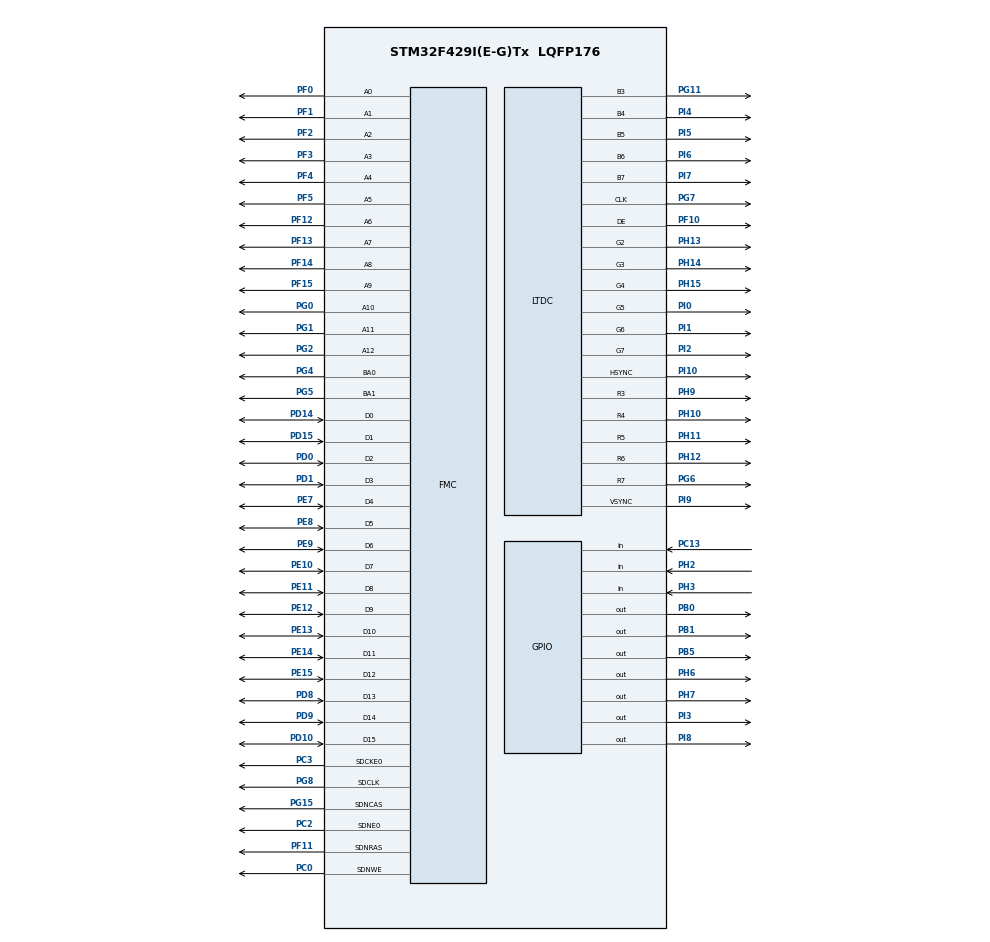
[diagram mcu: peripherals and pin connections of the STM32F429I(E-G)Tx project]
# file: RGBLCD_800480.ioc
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DMA2D.ColorMode=DMA2D_OUTPUT_RGB565
FMC.CASLatency1=FMC_SDRAM_CAS_LATENCY_3
FMC.ColumnBitsNumber1=FMC_SDRAM_COLUMN_BITS_NUM_9
FMC.ExitSelfRefreshDelay1=8
FMC.LoadToActiveDelay1=2
FMC.RCDDelay1=2
FMC.RPDelay1=2
FMC.RPDelay2=2
FMC.ReadBurst1=FMC_SDRAM_RBURST_ENABLE
FMC.ReadBurst2=FMC_SDRAM_RBURST_ENABLE
FMC.ReadPipeDelay1=FMC_SDRAM_RPIPE_DELAY_1
FMC.ReadPipeDelay2=FMC_SDRAM_RPIPE_DELAY_1
FMC.RowCycleDelay1=6
FMC.RowCycleDelay2=6
FMC.SDClockPeriod1=FMC_SDRAM_CLOCK_PERIOD_2
FMC.SDClockPeriod2=FMC_SDRAM_CLOCK_PERIOD_2
FMC.SelfRefreshTime1=6
FMC.WriteRecoveryTime1=4
LTDC.ActiveW=800
LTDC.Alpha_L0=255
LTDC.FBStartAdress_L0=0xC0000000
LTDC.HBP=88
LTDC.HFP=40
LTDC.HSync=1
LTDC.ImageHeight_L0=480
LTDC.ImageWidth_L0=800
LTDC.PixelFormat_L0=LTDC_PIXEL_FORMAT_RGB565
LTDC.PixelFormat_L1=LTDC_PIXEL_FORMAT_RGB565
LTDC.VBP=32
LTDC.VFP=13
LTDC.VSync=48
LTDC.WindowX1_L0=800
LTDC.WindowY1_L0=480
Mcu.Family=STM32F4
Mcu.Name=STM32F429I(E-G)Tx
Mcu.Package=LQFP176
NVIC.PriorityGroup=NVIC_PRIORITYGROUP_4
PA13.Mode=Serial_Wire
PA13.Signal=SYS_JTMS-SWDIO
PA14.Mode=Serial_Wire
PA14.Signal=SYS_JTCK-SWCLK
PB0.Signal=GPIO_Output
PB1.Signal=GPIO_Output
PB5.Signal=GPIO_Output
PC0.Signal=FMC_SDNWE
PC13.GPIO_PuPd=GPIO_PULLDOWN
PC13.Signal=GPIO_Input
PC2.Mode=SdramChipSelect1_1
PC2.Signal=FMC_SDNE0
PC3.Mode=SdramChipSelect1_1
PC3.Signal=FMC_SDCKE0
PD0.Signal=FMC_D2_DA2
PD1.Signal=FMC_D3_DA3
PD10.Signal=FMC_D15_DA15
PD14.Signal=FMC_D0_DA0
PD15.Signal=FMC_D1_DA1
PD8.Signal=FMC_D13_DA13
PD9.Signal=FMC_D14_DA14
PE10.Signal=FMC_D7_DA7
PE11.Signal=FMC_D8_DA8
PE12.Signal=FMC_D9_DA9
PE13.Signal=FMC_D10_DA10
PE14.Signal=FMC_D11_DA11
PE15.Signal=FMC_D12_DA12
PE7.Signal=FMC_D4_DA4
PE8.Signal=FMC_D5_DA5
PE9.Signal=FMC_D6_DA6
PF0.Signal=FMC_A0
PF1.Signal=FMC_A1
PF10.GPIO_Speed=GPIO_SPEED_FREQ_HIGH
PF10.Mode=RGB565
PF10.Signal=LTDC_DE
PF11.Signal=FMC_SDNRAS
PF12.Signal=FMC_A6
PF13.Signal=FMC_A7
PF14.Signal=FMC_A8
PF15.Signal=FMC_A9
PF2.Signal=FMC_A2
PF3.Signal=FMC_A3
PF4.Signal=FMC_A4
PF5.Signal=FMC_A5
PG0.Signal=FMC_A10
PG1.Signal=FMC_A11
PG11.GPIO_Speed=GPIO_SPEED_FREQ_HIGH
PG11.Mode=RGB565
PG11.Signal=LTDC_B3
PG15.Signal=FMC_SDNCAS
PG2.Signal=FMC_A12
PG4.Signal=FMC_A14_BA0
PG5.Signal=FMC_A15_BA1
PG6.GPIO_Speed=GPIO_SPEED_FREQ_HIGH
PG6.Mode=RGB565
PG6.Signal=LTDC_R7
PG7.GPIO_Speed=GPIO_SPEED_FREQ_HIGH
PG7.Mode=RGB565
PG7.Signal=LTDC_CLK
PG8.Signal=FMC_SDCLK
PH0/OSC_IN.Mode=HSE-External-Oscillator
PH0/OSC_IN.Signal=RCC_OSC_IN
PH1/OSC_OUT.Mode=HSE-External-Oscillator
PH1/OSC_OUT.Signal=RCC_OSC_OUT
PH10.GPIO_Speed=GPIO_SPEED_FREQ_HIGH
PH10.Mode=RGB565
PH10.Signal=LTDC_R4
PH11.GPIO_Speed=GPIO_SPEED_FREQ_HIGH
PH11.Mode=RGB565
PH11.Signal=LTDC_R5
PH12.GPIO_Speed=GPIO_SPEED_FREQ_HIGH
PH12.Mode=RGB565
PH12.Signal=LTDC_R6
PH13.GPIO_Speed=GPIO_SPEED_FREQ_HIGH
PH13.Mode=RGB565
PH13.Signal=LTDC_G2
PH14.GPIO_Speed=GPIO_SPEED_FREQ_HIGH
PH14.Mode=RGB565
PH14.Signal=LTDC_G3
PH15.GPIO_Speed=GPIO_SPEED_FREQ_HIGH
PH15.Mode=RGB565
PH15.Signal=LTDC_G4
PH2.GPIO_PuPd=GPIO_PULLDOWN
PH2.Signal=GPIO_Input
PH3.GPIO_PuPd=GPIO_PULLDOWN
PH3.Signal=GPIO_Input
PH6.GPIO_ModeDefaultOutputPP=GPIO_MODE_OUTPUT_OD
PH6.GPIO_PuPd=GPIO_NOPULL
PH6.GPIO_Speed=GPIO_SPEED_FREQ_HIGH
PH6.Signal=GPIO_Output
PH7.Signal=GPIO_Output
PH9.GPIO_Speed=GPIO_SPEED_FREQ_HIGH
PH9.Mode=RGB565
PH9.Signal=LTDC_R3
PI0.GPIO_Speed=GPIO_SPEED_FREQ_HIGH
PI0.Mode=RGB565
PI0.Signal=LTDC_G5
PI1.GPIO_Speed=GPIO_SPEED_FREQ_HIGH
PI1.Mode=RGB565
PI1.Signal=LTDC_G6
PI10.GPIO_Speed=GPIO_SPEED_FREQ_HIGH
PI10.Mode=RGB565
PI10.Signal=LTDC_HSYNC
PI2.GPIO_Speed=GPIO_SPEED_FREQ_HIGH
PI2.Mode=RGB565
PI2.Signal=LTDC_G7
PI3.GPIO_ModeDefaultOutputPP=GPIO_MODE_OUTPUT_OD
PI3.GPIO_PuPd=GPIO_NOPULL
PI3.GPIO_Speed=GPIO_SPEED_FREQ_HIGH
PI3.Signal=GPIO_Output
PI4.GPIO_Speed=GPIO_SPEED_FREQ_HIGH
PI4.Mode=RGB565
PI4.Signal=LTDC_B4
PI5.GPIO_Speed=GPIO_SPEED_FREQ_HIGH
PI5.Mode=RGB565
PI5.Signal=LTDC_B5
PI6.GPIO_Speed=GPIO_SPEED_FREQ_HIGH
PI6.Mode=RGB565
PI6.Signal=LTDC_B6
PI7.GPIO_Speed=GPIO_SPEED_FREQ_HIGH
PI7.Mode=RGB565
PI7.Signal=LTDC_B7
PI8.Signal=GPIO_Output
PI9.GPIO_Speed=GPIO_SPEED_FREQ_HIGH
PI9.Mode=RGB565
PI9.Signal=LTDC_VSYNC
ProjectManager.HeapSize=0x200
ProjectManager.StackSize=0x400
ProjectManager.TargetToolchain=Makefile
RCC.48MHZClocksFreq_Value=90000000
RCC.AHBFreq_Value=180000000
RCC.APB1CLKDivider=RCC_HCLK_DIV4
RCC.APB1Freq_Value=45000000
RCC.APB1TimFreq_Value=90000000
RCC.APB2CLKDivider=RCC_HCLK_DIV2
RCC.APB2Freq_Value=90000000
RCC.APB2TimFreq_Value=180000000
RCC.CortexFreq_Value=180000000
RCC.HCLKFreq_Value=180000000
RCC.HSE_VALUE=25000000
RCC.HSI_VALUE=16000000
RCC.LSE_VALUE=32768
RCC.PLLN=216
RCC.PLLSAIR=2
RCC.PLLSourceVirtual=RCC_PLLSOURCE_HSE
RCC.SYSCLKFreq_VALUE=180000000
RCC.SYSCLKSource=RCC_SYSCLKSOURCE_PLLCLK
RCC.VCOOutputFreq_Value=360000000
SH.FMC_A0.0=FMC_A0,13b-sda1
SH.FMC_A1.0=FMC_A1,13b-sda1
SH.FMC_A10.0=FMC_A10,13b-sda1
SH.FMC_A11.0=FMC_A11,13b-sda1
SH.FMC_A12.0=FMC_A12,13b-sda1
SH.FMC_A14_BA0.0=FMC_BA0,FourSdramBanks1
SH.FMC_A15_BA1.0=FMC_BA1,FourSdramBanks1
SH.FMC_A2.0=FMC_A2,13b-sda1
SH.FMC_A3.0=FMC_A3,13b-sda1
SH.FMC_A4.0=FMC_A4,13b-sda1
SH.FMC_A5.0=FMC_A5,13b-sda1
SH.FMC_A6.0=FMC_A6,13b-sda1
SH.FMC_A7.0=FMC_A7,13b-sda1
SH.FMC_A8.0=FMC_A8,13b-sda1
SH.FMC_A9.0=FMC_A9,13b-sda1
SH.FMC_D0_DA0.0=FMC_D0,sd-16b-d1
SH.FMC_D10_DA10.0=FMC_D10,sd-16b-d1
SH.FMC_D11_DA11.0=FMC_D11,sd-16b-d1
SH.FMC_D12_DA12.0=FMC_D12,sd-16b-d1
SH.FMC_D13_DA13.0=FMC_D13,sd-16b-d1
SH.FMC_D14_DA14.0=FMC_D14,sd-16b-d1
SH.FMC_D15_DA15.0=FMC_D15,sd-16b-d1
SH.FMC_D1_DA1.0=FMC_D1,sd-16b-d1
SH.FMC_D2_DA2.0=FMC_D2,sd-16b-d1
SH.FMC_D3_DA3.0=FMC_D3,sd-16b-d1
SH.FMC_D4_DA4.0=FMC_D4,sd-16b-d1
SH.FMC_D5_DA5.0=FMC_D5,sd-16b-d1
SH.FMC_D6_DA6.0=FMC_D6,sd-16b-d1
SH.FMC_D7_DA7.0=FMC_D7,sd-16b-d1
SH.FMC_D8_DA8.0=FMC_D8,sd-16b-d1
SH.FMC_D9_DA9.0=FMC_D9,sd-16b-d1
SH.FMC_SDCLK.0=FMC_SDCLK,13b-sda1
SH.FMC_SDNCAS.0=FMC_SDNCAS,13b-sda1
SH.FMC_SDNRAS.0=FMC_SDNRAS,13b-sda1
SH.FMC_SDNWE.0=FMC_SDNWE,13b-sda1
TIM6.Period=65535
TIM6.Prescaler=180-1
VP_DMA2D_VS_DMA2D.Mode=DMA2D_Activate
VP_TIM6_VS_ClockSourceINT.Mode=Enable_Timer
board=custom

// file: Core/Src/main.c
/* USER CODE BEGIN Header */
/**
 ******************************************************************************
 * @file           : main.c
 * @brief          : Main program body
 ******************************************************************************
 * @attention
 *
 * Copyright (c) 2023 STMicroelectronics.
 * All rights reserved.
 *
 * This software is licensed under terms that can be found in the LICENSE file
 * in the root directory of this software component.
 * If no LICENSE file comes with this software, it is provided AS-IS.
 *
 ******************************************************************************
 */
/* USER CODE END Header */
#include "main.h"
#include "dma2d.h"
#include "ltdc.h"
#include "tim.h"
#include "gpio.h"
#include "fmc.h"

/* USER CODE BEGIN Includes */
#include "lcd.h"
#include "math.h"
/* USER CODE END Includes */

/* USER CODE BEGIN PD */
#define KEY2_Pin           GPIO_PIN_13
#define KEY2_GPIO_Port     GPIOC
#define KEY_WkUP_Pin       GPIO_PIN_0
#define KEY_WkUP_GPIO_Port GPIOA
#define KEY1_Pin           GPIO_PIN_2
#define KEY1_GPIO_Port     GPIOH
#define KEY0_Pin           GPIO_PIN_3
#define KEY0_GPIO_Port     GPIOH
#define LED1_Pin           GPIO_PIN_0
#define LED1_GPIO_Port     GPIOB
#define LED0_Pin           GPIO_PIN_1
#define LED0_GPIO_Port     GPIOB
#define PI 3.1415926
/* USER CODE END PD */

void SystemClock_Config(void);

/* USER CODE BEGIN 0 */
void LCD_Test(void);

static float cube[8][3] = {
    {-32, -32, -32},
    {-32, +32, -32},
    {+32, +32, -32},
    {+32, -32, -32},
    {-32, -32, +32},
    {-32, +32, +32},
    {+32, +32, +32},
    {+32, -32, +32}
};

static uint8_t line_id[24] = {
    1, 2, 2, 3,
    3, 4, 4, 1,
    5, 6, 6, 7,
    7, 8, 8, 5,
    8, 4, 7, 3,
    6, 2, 5, 1
};
/* USER CODE END 0 */

int main(void)
{

    /* MCU Configuration--------------------------------------------------------*/

    /* Reset of all peripherals, Initializes the Flash interface and the Systick. */
    HAL_Init();

    /* Configure the system clock */
    SystemClock_Config();

    /* Initialize all configured peripherals */
    MX_GPIO_Init();
    MX_LTDC_Init();
    MX_DMA2D_Init();
    MX_FMC_Init();
    MX_TIM6_Init();
    /* USER CODE BEGIN 2 */
    MX_FMC_Init();
    MX_LTDC_Init();
    LCD_Init();
    LCD_Test();
    /* USER CODE END 2 */

    /* Infinite loop */
    while (1) {

    }
}

void SystemClock_Config(void)
{
    RCC_OscInitTypeDef RCC_OscInitStruct = {0};
    RCC_ClkInitTypeDef RCC_ClkInitStruct = {0};

    /** Configure the main internal regulator output voltage
     */
    __HAL_RCC_PWR_CLK_ENABLE();
    __HAL_PWR_VOLTAGESCALING_CONFIG(PWR_REGULATOR_VOLTAGE_SCALE1);

    /** Initializes the RCC Oscillators according to the specified parameters
     * in the RCC_OscInitTypeDef structure.
     */
    RCC_OscInitStruct.OscillatorType = RCC_OSCILLATORTYPE_HSE;
    RCC_OscInitStruct.HSEState       = RCC_HSE_ON;
    RCC_OscInitStruct.PLL.PLLState   = RCC_PLL_ON;
    RCC_OscInitStruct.PLL.PLLSource  = RCC_PLLSOURCE_HSE;
    RCC_OscInitStruct.PLL.PLLM       = 16;
    RCC_OscInitStruct.PLL.PLLN       = 216;
    RCC_OscInitStruct.PLL.PLLP       = RCC_PLLP_DIV2;
    RCC_OscInitStruct.PLL.PLLQ       = 4;
    if (HAL_RCC_OscConfig(&RCC_OscInitStruct) != HAL_OK) {
        Error_Handler();
    }

    /** Activate the Over-Drive mode
     */
    if (HAL_PWREx_EnableOverDrive() != HAL_OK) {
        Error_Handler();
    }

    /** Initializes the CPU, AHB and APB buses clocks
     */
    RCC_ClkInitStruct.ClockType      = RCC_CLOCKTYPE_HCLK | RCC_CLOCKTYPE_SYSCLK | RCC_CLOCKTYPE_PCLK1 | RCC_CLOCKTYPE_PCLK2;
    RCC_ClkInitStruct.SYSCLKSource   = RCC_SYSCLKSOURCE_PLLCLK;
    RCC_ClkInitStruct.AHBCLKDivider  = RCC_SYSCLK_DIV1;
    RCC_ClkInitStruct.APB1CLKDivider = RCC_HCLK_DIV4;
    RCC_ClkInitStruct.APB2CLKDivider = RCC_HCLK_DIV2;

    if (HAL_RCC_ClockConfig(&RCC_ClkInitStruct, FLASH_LATENCY_5) != HAL_OK) {
        Error_Handler();
    }
}

/* USER CODE BEGIN 4 */

static float *demo_matconv(float *a, float b[3][3])
{
    float res[3];
    uint8_t res_index;
    uint8_t a_index;

    for (res_index = 0; res_index < 3; res_index++) {
        res[res_index] = b[res_index][0] * a[0] + b[res_index][1] * a[1] + b[res_index][2] * a[2];
    }

    for (a_index = 0; a_index < 3; a_index++) {
        a[a_index] = res[a_index];
    }

    return a;
}

static void demo_rotate(float *point, float x, float y, float z)
{
    float rx[3][3];
    float ry[3][3];
    float rz[3][3];

    x /= PI;
    y /= PI;
    z /= PI;

    rx[0][0] = cos(x);
    rx[0][1] = 0;
    rx[0][2] = sin(x);
    rx[1][0] = 0;
    rx[1][1] = 1;
    rx[1][2] = 0;
    rx[2][0] = -sin(x);
    rx[2][1] = 0;
    rx[2][2] = cos(x);

    ry[0][0] = 1;
    ry[0][1] = 0;
    ry[0][2] = 0;
    ry[1][0] = 0;
    ry[1][1] = cos(y);
    ry[1][2] = -sin(y);
    ry[2][0] = 0;
    ry[2][1] = sin(y);
    ry[2][2] = cos(y);

    rz[0][0] = cos(z);
    rz[0][1] = -sin(z);
    rz[0][2] = 0;
    rz[1][0] = sin(z);
    rz[1][1] = cos(z);
    rz[1][2] = 0;
    rz[2][0] = 0;
    rz[2][1] = 0;
    rz[2][2] = 1;

    demo_matconv(demo_matconv(demo_matconv(point, rz), ry), rx);
}

void LCD_Test(void)
{
    uint8_t ret;
    uint16_t pid;

    ret = LCD_Init();
    pid = LCD_Get_PID();
    if ((ret != 0) || (pid != LCD_PID_4384)) {
    }
    LCD_Clear(LCD_WHITE);
    LCD_Show_String(10, 10, LCD_Get_Width(), 32, "STM32", LCD_FONT_32, LCD_RED);
    LCD_Show_String(10, 42, LCD_Get_Width(), 24, "ATK-MD0430R-800480", LCD_FONT_24, LCD_RED);
    LCD_Show_String(10, 66, LCD_Get_Width(), 16, "ATOM@ALIENTEK", LCD_FONT_16, LCD_RED);
    while (1) {
        uint8_t point_index;
        uint8_t line_index;
        static uint16_t x = 57;
        static uint16_t y = 139;
#if (LCD_USING_TOUCH != 0)
        static LCD_touch_point_t point[1];

        if (LCD_Touch_Scan(point, sizeof(point) / sizeof(point[0])) == sizeof(point) / sizeof(point[0])) {
            if ((point[0].x > 56) && (point[0].x < (LCD_Get_Width() - 56)) && (point[0].y > 138) && (point[0].y < (LCD_Get_Height() - 56))) {
                x = point[0].x;
                y = point[0].y;
            }
        }
#endif

        for (point_index = 0; point_index < 8; point_index++) {
            demo_rotate(cube[point_index], 0.05f, 0.03f, 0.02f);
        }

        for (line_index = 0; line_index < 24; line_index += 2) {
            LCD_Draw_Line(x + cube[line_id[line_index] - 1][0],
                          y + cube[line_id[line_index] - 1][1],
                          x + cube[line_id[line_index + 1] - 1][0],
                          y + cube[line_id[line_index + 1] - 1][1],
                          LCD_BLUE);
        }

        HAL_Delay(20);

        LCD_Fill(x - 56, y - 56, x + 56, y + 56, LCD_WHITE);
    }
}
/* USER CODE END 4 */

void Error_Handler(void)
{
    __disable_irq();
    while (1) {
    }
}
